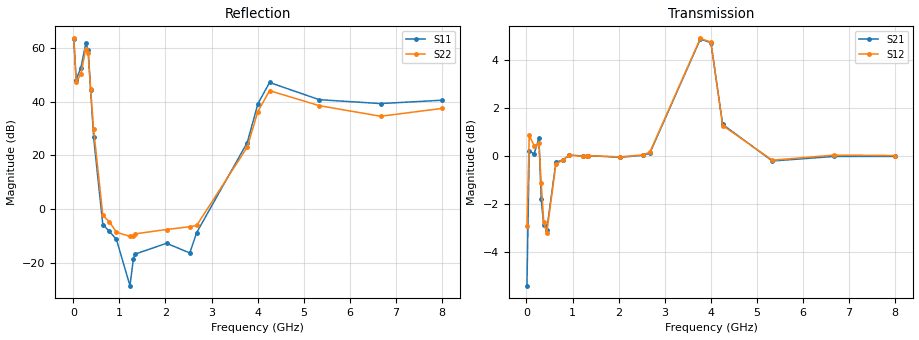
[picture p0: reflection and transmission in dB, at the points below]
!Agilent Technologies,N5230A,US43500312,A.07.50.67
!Agilent N5230A: A.07.50.67
!Date: Tuesday, June 09, 2015 15:35:54
!Correction: S11(Full 2 Port(1,2))
!S21(Full 2 Port(1,2))
!S12(Full 2 Port(1,2))
!S22(Full 2 Port(1,2))
!S2P File: Measurements: S11, S21, S12, S22:
# Hz S  MA  R 50
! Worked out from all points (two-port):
!   1601 points, 10 MHz to 8 GHz, reference 50 ohm
!   highest |S21| = 4.89 dB at 3.775 GHz (marker M1); lowest = -5.4 dB at 10 MHz (marker M2)
!   |S21| within 3 dB of the highest: 234.3 MHz to 240.3 MHz (5.935 MHz wide, 2.5 % of centre); 3.536 GHz to 4.233 GHz (697.1 MHz wide, 17.9 % of centre) (the widest 2 of 6)
!   lowest |S11| = -28.5 dB at 1.228 GHz (marker M3), VSWR 1.08, Z = 52.2 + j3.12 ohm
!   |S11| at or under -10 dB: 801.7 MHz to 966 MHz (164.3 MHz wide, 18.6 % of centre); 1.045 GHz to 2.094 GHz (1.05 GHz wide, 66.9 % of centre); 2.413 GHz to 2.656 GHz (242.9 MHz wide, 9.58 % of centre) (the widest 3 of 4)
!   |S22| runs from -14.0 to 63.6 dB; largest |S21 - S12| = 0.6
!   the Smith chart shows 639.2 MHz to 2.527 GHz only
!   S11 on the Smith chart (normalised r, x): 639.2 MHz: 0.41, +0.48; 784 MHz: 0.45, +0.10; 933.8 MHz: 1.03, -0.58; 1.303 GHz: 0.87, +0.18; 2.022 GHz: 0.63, +0.06; 2.527 GHz: 0.77, -0.14
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1e7  1499 171.1  0.5361 -27.6  0.7159 -82.5  1520 -19.4
5.99375e7  257.1 326.2  1.027 -0.1  1.106 3.5  231.6 92.3
1.648062e8  432.8 402.0  1.01 2.6  1.052 1.5  332.9 124.0
2.69675e8  1222 384.8  1.091 -6.4  1.063 -10.1  983.1 102.1
3.196125e8  934.7 423.8  0.814 14.7  0.8797 15.0  829 147.9
3.745438e8  165.2 437.8  0.7169 11.1  0.728 8.3  175.5 178.5
4.394625e8  21.79 422.3  0.7011 10.2  0.6911 10.4  30.9 199.3
6.392125e8  0.5131 481.9  0.9711 20.9  0.9621 21.1  0.7683 377.7
7.840312e8  0.3851 525.6  0.982 16.0  0.9813 15.9  0.5801 459.3
9.338438e8  0.2746 649.0  1.005 15.4  1.004 15.4  0.3722 579.8
1.228475e9  0.03758 772.6  1.001 16.3  0.9988 16.4  0.3111 700.8
1.303381e9  0.1192 839.4  1.003 16.3  1.002 16.4  0.3197 746.9
1.343331e9  0.1458 846.6  1.003 16.3  1.003 16.3  0.3474 765.2
2.022481e9  0.2319 889.6  0.9944 15.3  0.9966 15.3  0.4183 1046.4
2.52685e9  0.1528 936.0  1.004 17.1  1.006 17.0  0.4712 1164.1
2.676662e9  0.3659 1028.9  1.014 17.2  1.019 17.2  0.4975 1228.5
3.775288e9  17.44 1401.5  1.757 18.8  1.763 19.0  14.31 1532.2
4.005e9  91.4 1398.9  1.726 1.2  1.731 1.2  65.77 1522.7
4.259681e9  229 1345.4  1.165 -19.4  1.159 -19.7  161.3 1459.6
5.338331e9  109.6 1322.8  0.977 2.6  0.9809 2.5  84.79 1401.5
6.671662e9  92.75 1359.5  0.9986 2.3  1.005 2.7  53.85 1340.8
8e9  107 1387.3  0.9988 1.7  1.003 1.9  75.19 1308.4
